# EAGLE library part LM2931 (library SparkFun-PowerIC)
LDO regulator with reverse battery protection- very durable!

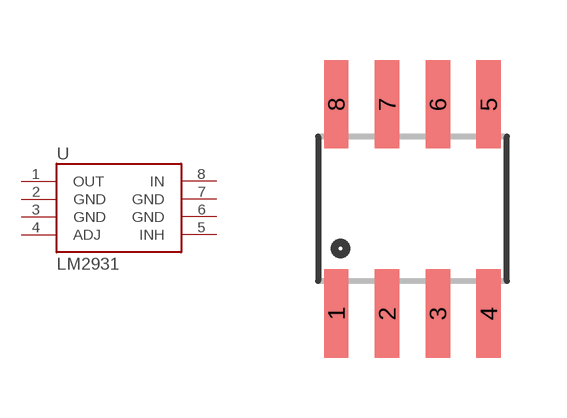
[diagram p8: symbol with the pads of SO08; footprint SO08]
Designator prefix -

## LM2931  [SO08]
1  OUT
2  GND
3  GND
4  ADJ
5  INH
6  GND
7  GND
8  IN

## Footprint SO08 (pad centres in mm)
Small Outline Package Fits JEDEC packages (narrow SOIC-8)
smd 0.61 x 2.21: 1 -1.905,-2.616; 2 -0.635,-2.616; 3 0.635,-2.616; 4 1.905,-2.616; 5 1.905,2.616; 6 0.635,2.616; 7 -0.635,2.616; 8 -1.905,2.616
